One B-rep face of a CAD part: STEP entity #394.
In plain terms, the planar face has unit normal (1, 0, 0).
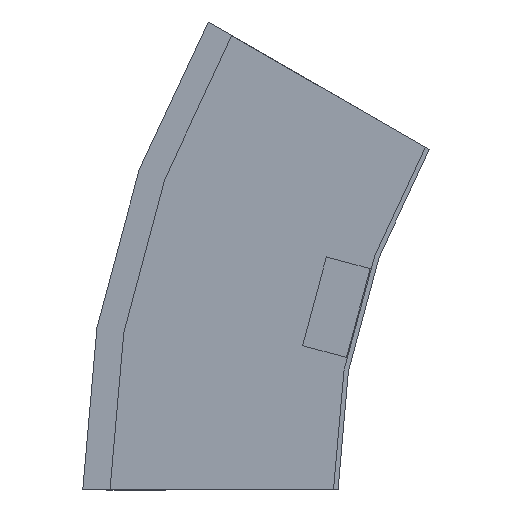
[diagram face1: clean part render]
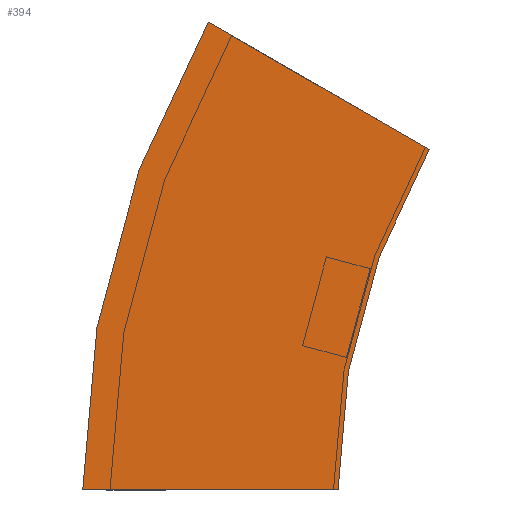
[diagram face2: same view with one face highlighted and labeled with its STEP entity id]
Its self-contained STEP definition (entity closure, numbers rounded to 3 decimals):
#9 = EDGE_CURVE ( 'NONE', #438, #523, #444, .T. ) ;
#13 = DIRECTION ( 'NONE',  ( 0., 0.866, 0.5 ) ) ;
#16 = DIRECTION ( 'NONE',  ( 0., 0., -1. ) ) ;
#30 = CIRCLE ( 'NONE', #207, 300. ) ;
#52 = ORIENTED_EDGE ( 'NONE', *, *, #9, .F. ) ;
#53 = CARTESIAN_POINT ( 'NONE',  ( 0., 112.5, 0. ) ) ;
#56 = CARTESIAN_POINT ( 'NONE',  ( 0., -40.192, 150. ) ) ;
#100 = DIRECTION ( 'NONE',  ( 0., 1., 0. ) ) ;
#120 = CARTESIAN_POINT ( 'NONE',  ( 0., -300., 0. ) ) ;
#133 = DIRECTION ( 'NONE',  ( 1., 0., 0. ) ) ;
#139 = CARTESIAN_POINT ( 'NONE',  ( 0., 0., 0. ) ) ;
#141 = PLANE ( 'NONE',  #185 ) ;
#172 = EDGE_CURVE ( 'NONE', #536, #523, #278, .T. ) ;
#177 = ORIENTED_EDGE ( 'NONE', *, *, #308, .F. ) ;
#185 = AXIS2_PLACEMENT_3D ( 'NONE', #139, #364, #16 ) ;
#207 = AXIS2_PLACEMENT_3D ( 'NONE', #120, #133, #100 ) ;
#211 = DIRECTION ( 'NONE',  ( 0., 1., 0. ) ) ;
#274 = CARTESIAN_POINT ( 'NONE',  ( 0., 57.235, 206.25 ) ) ;
#276 = ORIENTED_EDGE ( 'NONE', *, *, #172, .T. ) ;
#278 = CIRCLE ( 'NONE', #561, 412.5 ) ;
#292 = CARTESIAN_POINT ( 'NONE',  ( 0., -300., 0. ) ) ;
#308 = EDGE_CURVE ( 'NONE', #486, #438, #30, .T. ) ;
#338 = DIRECTION ( 'NONE',  ( 1., 0., 0. ) ) ;
#364 = DIRECTION ( 'NONE',  ( 1., 0., 0. ) ) ;
#367 = LINE ( 'NONE', #447, #516 ) ;
#371 = DIRECTION ( 'NONE',  ( 0., 1., 0. ) ) ;
#394 = ADVANCED_FACE ( 'NONE', ( #530 ), #141, .T. ) ;
#430 = EDGE_CURVE ( 'NONE', #486, #536, #367, .T. ) ;
#438 = VERTEX_POINT ( 'NONE', #538 ) ;
#444 = LINE ( 'NONE', #56, #509 ) ;
#447 = CARTESIAN_POINT ( 'NONE',  ( 0., 0., 0. ) ) ;
#469 = CARTESIAN_POINT ( 'NONE',  ( 0., 0., 0. ) ) ;
#486 = VERTEX_POINT ( 'NONE', #469 ) ;
#495 = ORIENTED_EDGE ( 'NONE', *, *, #430, .T. ) ;
#509 = VECTOR ( 'NONE', #13, 1000. ) ;
#516 = VECTOR ( 'NONE', #371, 1000. ) ;
#521 = EDGE_LOOP ( 'NONE', ( #276, #52, #177, #495 ) ) ;
#523 = VERTEX_POINT ( 'NONE', #274 ) ;
#530 = FACE_OUTER_BOUND ( 'NONE', #521, .T. ) ;
#536 = VERTEX_POINT ( 'NONE', #53 ) ;
#538 = CARTESIAN_POINT ( 'NONE',  ( 0., -40.192, 150. ) ) ;
#561 = AXIS2_PLACEMENT_3D ( 'NONE', #292, #338, #211 ) ;
